VERSION 5.7 ;
  NOWIREEXTENSIONATPIN ON ;
  DIVIDERCHAR "/" ;
  BUSBITCHARS "[]" ;
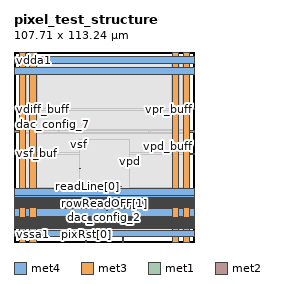
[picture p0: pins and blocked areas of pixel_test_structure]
MACRO pixel_test_structure
  CLASS BLOCK ;
  FOREIGN pixel_test_structure ;
  ORIGIN 0.000 0.000 ;
  SIZE 107.710 BY 113.240 ;
  PIN vssa1
    ANTENNAGATEAREA 6.400000 ;
    ANTENNADIFFAREA 1154.272583 ;
    PORT
      LAYER met4 ;
        RECT 0.000 99.725 107.710 103.725 ;
    END
    PORT
      LAYER met4 ;
        RECT 0.000 27.985 107.710 31.985 ;
    END
    PORT
      LAYER met3 ;
        RECT 9.445 0.000 13.445 113.240 ;
    END
    PORT
      LAYER met3 ;
        RECT 94.265 0.000 98.265 113.240 ;
    END
  END vssa1
  PIN vdda1
    ANTENNADIFFAREA 106.722198 ;
    PORT
      LAYER met1 ;
        RECT 46.935 65.910 46.945 65.920 ;
    END
    PORT
      LAYER met2 ;
        RECT 52.915 103.770 52.925 103.780 ;
    END
    PORT
      LAYER met4 ;
        RECT 0.000 106.310 107.710 110.310 ;
    END
    PORT
      LAYER met4 ;
        RECT 0.000 3.000 107.710 7.000 ;
    END
    PORT
      LAYER met3 ;
        RECT 3.000 0.000 6.980 113.240 ;
    END
    PORT
      LAYER met3 ;
        RECT 100.730 0.000 104.710 113.240 ;
    END
  END vdda1
  PIN rowReadON[0]
    ANTENNAGATEAREA 0.252000 ;
    PORT
      LAYER met2 ;
        RECT 41.610 47.510 41.620 47.520 ;
    END
    PORT
      LAYER met4 ;
        RECT 0.000 20.355 107.710 21.085 ;
    END
    PORT
      LAYER met3 ;
        RECT 41.240 21.455 41.250 21.465 ;
    END
    PORT
      LAYER met3 ;
        RECT 41.240 43.455 41.250 43.465 ;
    END
  END rowReadON[0]
  PIN rowReadOFF[0]
    ANTENNAGATEAREA 0.126000 ;
    PORT
      LAYER met2 ;
        RECT 41.395 47.895 41.405 47.905 ;
    END
    PORT
      LAYER met4 ;
        RECT 0.000 21.585 107.710 22.315 ;
    END
    PORT
      LAYER met3 ;
        RECT 40.600 22.860 40.610 22.870 ;
    END
    PORT
      LAYER met3 ;
        RECT 40.600 43.400 40.610 43.410 ;
    END
  END rowReadOFF[0]
  PIN rowReadOFF[1]
    ANTENNAGATEAREA 0.126000 ;
    PORT
      LAYER met2 ;
        RECT 40.870 45.425 40.880 45.435 ;
    END
    PORT
      LAYER met4 ;
        RECT 0.000 22.840 107.710 23.570 ;
    END
    PORT
      LAYER met3 ;
        RECT 39.985 24.200 39.995 24.210 ;
    END
    PORT
      LAYER met3 ;
        RECT 39.985 43.370 39.995 43.380 ;
    END
  END rowReadOFF[1]
  PIN rowReadON[1]
    ANTENNAGATEAREA 0.252000 ;
    PORT
      LAYER met2 ;
        RECT 40.890 45.850 40.900 45.860 ;
    END
    PORT
      LAYER met4 ;
        RECT 0.000 24.070 107.710 24.850 ;
    END
    PORT
      LAYER met3 ;
        RECT 39.330 25.970 39.340 25.980 ;
    END
    PORT
      LAYER met3 ;
        RECT 39.330 43.530 39.340 43.540 ;
    END
  END rowReadON[1]
  PIN vssc1
    ANTENNADIFFAREA 2.373000 ;
    PORT
      LAYER met4 ;
        RECT 0.000 15.360 107.710 19.855 ;
    END
  END vssc1
  PIN vsf_buf
    ANTENNAGATEAREA 38.399998 ;
    ANTENNADIFFAREA 13.040000 ;
    PORT
      LAYER met4 ;
        RECT 0.000 52.295 3.000 53.025 ;
    END
  END vsf_buf
  PIN vdiff_buff
    ANTENNAGATEAREA 38.399998 ;
    ANTENNADIFFAREA 13.040000 ;
    PORT
      LAYER met4 ;
        RECT 0.000 78.685 3.000 79.415 ;
    END
  END vdiff_buff
  PIN vpr_buff
    ANTENNAGATEAREA 38.399998 ;
    ANTENNADIFFAREA 13.040000 ;
    PORT
      LAYER met4 ;
        RECT 104.710 78.685 107.710 79.415 ;
    END
  END vpr_buff
  PIN dac_config_7
    ANTENNAGATEAREA 32.000000 ;
    PORT
      LAYER met1 ;
        RECT 71.785 63.615 71.795 63.625 ;
    END
    PORT
      LAYER met1 ;
        RECT 71.790 68.215 71.800 68.225 ;
    END
    PORT
      LAYER met1 ;
        RECT 36.125 63.635 36.135 63.645 ;
    END
    PORT
      LAYER met1 ;
        RECT 35.860 68.190 35.870 68.200 ;
    END
    PORT
      LAYER met2 ;
        RECT 31.765 65.905 31.775 65.915 ;
    END
    PORT
      LAYER met4 ;
        RECT 80.695 65.850 80.705 65.860 ;
    END
    PORT
      LAYER met4 ;
        RECT 27.005 65.850 27.015 65.860 ;
    END
    PORT
      LAYER met4 ;
        RECT 0.000 65.090 3.000 66.620 ;
    END
    PORT
      LAYER met4 ;
        RECT 104.710 65.090 107.710 66.620 ;
    END
  END dac_config_7
  PIN vpd_buff
    ANTENNAGATEAREA 38.399998 ;
    ANTENNADIFFAREA 13.040000 ;
    PORT
      LAYER met4 ;
        RECT 104.710 52.295 107.710 53.025 ;
    END
  END vpd_buff
  PIN readOut[1]
    ANTENNADIFFAREA 0.891000 ;
    PORT
      LAYER met4 ;
        RECT 0.000 26.705 107.710 27.485 ;
    END
  END readOut[1]
  PIN readOut[0]
    ANTENNADIFFAREA 0.891000 ;
    PORT
      LAYER met4 ;
        RECT 0.000 25.425 107.710 26.205 ;
    END
  END readOut[0]
  PIN dac_config_2
    ANTENNAGATEAREA 9.000000 ;
    PORT
      LAYER met4 ;
        RECT 0.000 14.130 107.710 14.860 ;
    END
    PORT
      LAYER met3 ;
        RECT 55.425 18.835 55.435 18.845 ;
    END
  END dac_config_2
  PIN dac_config_5
    ANTENNAGATEAREA 2.520000 ;
    PORT
      LAYER met4 ;
        RECT 0.000 12.875 107.710 13.605 ;
    END
    PORT
      LAYER met3 ;
        RECT 54.795 13.845 54.805 13.855 ;
    END
  END dac_config_5
  PIN dac_config_3
    ANTENNAGATEAREA 0.300000 ;
    PORT
      LAYER met4 ;
        RECT 0.000 11.645 107.710 12.375 ;
    END
    PORT
      LAYER met3 ;
        RECT 54.165 12.575 54.175 12.585 ;
    END
  END dac_config_3
  PIN dac_config_4
    ANTENNAGATEAREA 2.520000 ;
    PORT
      LAYER met4 ;
        RECT 0.000 10.415 107.710 11.145 ;
    END
    PORT
      LAYER met3 ;
        RECT 53.535 11.425 53.545 11.435 ;
    END
  END dac_config_4
  PIN dac_config_1
    ANTENNAGATEAREA 9.000000 ;
    PORT
      LAYER met4 ;
        RECT 0.000 9.160 107.710 9.890 ;
    END
    PORT
      LAYER met3 ;
        RECT 52.905 10.200 52.915 10.210 ;
    END
  END dac_config_1
  PIN dac_config_0
    ANTENNAGATEAREA 9.000000 ;
    PORT
      LAYER met4 ;
        RECT 0.000 7.930 107.710 8.660 ;
    END
    PORT
      LAYER met3 ;
        RECT 52.275 8.945 52.285 8.955 ;
    END
  END dac_config_0
  PIN pixRst[1]
    ANTENNAGATEAREA 0.126000 ;
    PORT
      LAYER met3 ;
        RECT 64.475 0.000 65.075 3.000 ;
    END
  END pixRst[1]
  PIN pixRst[0]
    ANTENNAGATEAREA 0.126000 ;
    PORT
      LAYER met3 ;
        RECT 42.635 0.000 43.235 3.000 ;
    END
  END pixRst[0]
  PIN vpd
    ANTENNAGATEAREA 19.326000 ;
    ANTENNADIFFAREA 0.318100 ;
    PORT
      LAYER met1 ;
        RECT 47.750 59.720 47.760 59.730 ;
    END
    PORT
      LAYER met2 ;
        RECT 68.850 48.270 68.860 48.280 ;
    END
    PORT
      LAYER met2 ;
        RECT 68.865 60.070 68.875 60.080 ;
    END
  END vpd
  PIN vpr
    ANTENNAGATEAREA 19.455000 ;
    ANTENNADIFFAREA 0.276000 ;
    PORT
      LAYER met1 ;
        RECT 46.870 59.720 46.880 59.730 ;
    END
    PORT
      LAYER met2 ;
        RECT 68.855 83.480 68.865 83.490 ;
    END
    PORT
      LAYER met2 ;
        RECT 68.835 61.585 68.845 61.595 ;
    END
  END vpr
  PIN vdiff
    ANTENNAGATEAREA 23.699999 ;
    ANTENNADIFFAREA 1.026000 ;
    PORT
      LAYER met1 ;
        RECT 43.735 59.690 43.745 59.700 ;
    END
    PORT
      LAYER met2 ;
        RECT 38.870 83.510 38.880 83.520 ;
    END
    PORT
      LAYER met2 ;
        RECT 38.960 59.850 38.970 59.860 ;
    END
  END vdiff
  PIN readLine[0]
    ANTENNAGATEAREA 1.247500 ;
    ANTENNADIFFAREA 0.685000 ;
    PORT
      LAYER met2 ;
        RECT 43.645 32.950 43.655 32.960 ;
    END
  END readLine[0]
  PIN readLine[1]
    ANTENNAGATEAREA 1.247500 ;
    ANTENNADIFFAREA 0.685000 ;
    PORT
      LAYER met2 ;
        RECT 63.770 32.795 63.780 32.805 ;
    END
  END readLine[1]
  PIN vsf
    ANTENNAGATEAREA 19.199999 ;
    ANTENNADIFFAREA 0.252000 ;
    PORT
      LAYER met2 ;
        RECT 39.025 58.305 39.035 58.315 ;
    END
    PORT
      LAYER met2 ;
        RECT 38.970 48.265 38.980 48.275 ;
    END
  END vsf
  OBS
      LAYER nwell ;
        RECT 7.360 23.735 100.350 106.315 ;
      LAYER li1 ;
        RECT 7.490 23.865 100.220 106.185 ;
      LAYER met1 ;
        RECT 7.430 68.505 100.280 106.245 ;
        RECT 7.430 68.480 71.510 68.505 ;
        RECT 7.430 67.910 35.580 68.480 ;
        RECT 36.150 67.935 71.510 68.480 ;
        RECT 72.080 67.935 100.280 68.505 ;
        RECT 36.150 67.910 100.280 67.935 ;
        RECT 7.430 66.200 100.280 67.910 ;
        RECT 7.430 65.630 46.655 66.200 ;
        RECT 47.225 65.630 100.280 66.200 ;
        RECT 7.430 63.925 100.280 65.630 ;
        RECT 7.430 63.355 35.845 63.925 ;
        RECT 36.415 63.905 100.280 63.925 ;
        RECT 36.415 63.355 71.505 63.905 ;
        RECT 7.430 63.335 71.505 63.355 ;
        RECT 72.075 63.335 100.280 63.905 ;
        RECT 7.430 60.010 100.280 63.335 ;
        RECT 7.430 59.980 46.590 60.010 ;
        RECT 7.430 59.410 43.455 59.980 ;
        RECT 44.025 59.440 46.590 59.980 ;
        RECT 47.160 59.440 47.470 60.010 ;
        RECT 48.040 59.440 100.280 60.010 ;
        RECT 44.025 59.410 100.280 59.440 ;
        RECT 7.430 23.225 100.280 59.410 ;
      LAYER met2 ;
        RECT 7.695 104.060 100.015 110.310 ;
        RECT 7.695 103.490 52.635 104.060 ;
        RECT 53.205 103.490 100.015 104.060 ;
        RECT 7.695 83.800 100.015 103.490 ;
        RECT 7.695 83.230 38.590 83.800 ;
        RECT 39.160 83.770 100.015 83.800 ;
        RECT 39.160 83.230 68.575 83.770 ;
        RECT 7.695 83.200 68.575 83.230 ;
        RECT 69.145 83.200 100.015 83.770 ;
        RECT 7.695 66.195 100.015 83.200 ;
        RECT 7.695 65.625 31.485 66.195 ;
        RECT 32.055 65.625 100.015 66.195 ;
        RECT 7.695 61.875 100.015 65.625 ;
        RECT 7.695 61.305 68.555 61.875 ;
        RECT 69.125 61.305 100.015 61.875 ;
        RECT 7.695 60.360 100.015 61.305 ;
        RECT 7.695 60.140 68.585 60.360 ;
        RECT 7.695 59.570 38.680 60.140 ;
        RECT 39.250 59.790 68.585 60.140 ;
        RECT 69.155 59.790 100.015 60.360 ;
        RECT 39.250 59.570 100.015 59.790 ;
        RECT 7.695 58.595 100.015 59.570 ;
        RECT 7.695 58.025 38.745 58.595 ;
        RECT 39.315 58.025 100.015 58.595 ;
        RECT 7.695 48.560 100.015 58.025 ;
        RECT 7.695 48.555 68.570 48.560 ;
        RECT 7.695 47.985 38.690 48.555 ;
        RECT 39.260 48.185 68.570 48.555 ;
        RECT 39.260 47.985 41.115 48.185 ;
        RECT 7.695 47.615 41.115 47.985 ;
        RECT 41.685 47.990 68.570 48.185 ;
        RECT 69.140 47.990 100.015 48.560 ;
        RECT 41.685 47.800 100.015 47.990 ;
        RECT 7.695 47.230 41.330 47.615 ;
        RECT 41.900 47.230 100.015 47.800 ;
        RECT 7.695 46.140 100.015 47.230 ;
        RECT 7.695 45.715 40.610 46.140 ;
        RECT 7.695 45.145 40.590 45.715 ;
        RECT 41.180 45.570 100.015 46.140 ;
        RECT 41.160 45.145 100.015 45.570 ;
        RECT 7.695 33.240 100.015 45.145 ;
        RECT 7.695 32.670 43.365 33.240 ;
        RECT 43.935 33.085 100.015 33.240 ;
        RECT 43.935 32.670 63.490 33.085 ;
        RECT 7.695 32.515 63.490 32.670 ;
        RECT 64.060 32.515 100.015 33.085 ;
        RECT 7.695 23.225 100.015 32.515 ;
      LAYER met3 ;
        RECT 7.380 3.000 9.045 110.270 ;
        RECT 13.845 43.940 93.865 110.270 ;
        RECT 13.845 43.130 38.930 43.940 ;
        RECT 39.740 43.865 93.865 43.940 ;
        RECT 39.740 43.810 40.840 43.865 ;
        RECT 39.740 43.780 40.200 43.810 ;
        RECT 13.845 42.970 39.585 43.130 ;
        RECT 41.650 43.055 93.865 43.865 ;
        RECT 41.010 43.000 93.865 43.055 ;
        RECT 40.395 42.970 93.865 43.000 ;
        RECT 13.845 26.380 93.865 42.970 ;
        RECT 13.845 25.570 38.930 26.380 ;
        RECT 39.740 25.570 93.865 26.380 ;
        RECT 13.845 24.610 93.865 25.570 ;
        RECT 13.845 23.800 39.585 24.610 ;
        RECT 40.395 23.800 93.865 24.610 ;
        RECT 13.845 23.270 93.865 23.800 ;
        RECT 13.845 22.460 40.200 23.270 ;
        RECT 41.010 22.460 93.865 23.270 ;
        RECT 13.845 21.865 93.865 22.460 ;
        RECT 13.845 21.055 40.840 21.865 ;
        RECT 41.650 21.055 93.865 21.865 ;
        RECT 13.845 19.245 93.865 21.055 ;
        RECT 13.845 18.435 55.025 19.245 ;
        RECT 55.835 18.435 93.865 19.245 ;
        RECT 13.845 14.255 93.865 18.435 ;
        RECT 13.845 13.445 54.395 14.255 ;
        RECT 55.205 13.445 93.865 14.255 ;
        RECT 13.845 12.985 93.865 13.445 ;
        RECT 13.845 12.175 53.765 12.985 ;
        RECT 54.575 12.175 93.865 12.985 ;
        RECT 13.845 11.835 93.865 12.175 ;
        RECT 13.845 11.025 53.135 11.835 ;
        RECT 53.945 11.025 93.865 11.835 ;
        RECT 13.845 10.610 93.865 11.025 ;
        RECT 13.845 9.800 52.505 10.610 ;
        RECT 53.315 9.800 93.865 10.610 ;
        RECT 13.845 9.355 93.865 9.800 ;
        RECT 13.845 8.545 51.875 9.355 ;
        RECT 52.685 8.545 93.865 9.355 ;
        RECT 13.845 3.400 93.865 8.545 ;
        RECT 13.845 3.000 42.235 3.400 ;
        RECT 43.635 3.000 64.075 3.400 ;
        RECT 65.475 3.000 93.865 3.400 ;
        RECT 98.665 3.000 100.330 110.270 ;
      LAYER met4 ;
        RECT 3.400 78.285 104.310 79.415 ;
        RECT 3.000 67.020 104.710 78.285 ;
        RECT 3.400 66.260 104.310 67.020 ;
        RECT 3.400 65.450 26.605 66.260 ;
        RECT 27.415 65.450 80.295 66.260 ;
        RECT 81.105 65.450 104.310 66.260 ;
        RECT 3.400 64.690 104.310 65.450 ;
        RECT 3.000 53.425 104.710 64.690 ;
        RECT 3.400 51.895 104.310 53.425 ;
        RECT 3.000 32.385 104.710 51.895 ;
      LAYER met5 ;
        RECT 39.165 31.985 68.545 61.365 ;
  END
END pixel_test_structure
END LIBRARY

